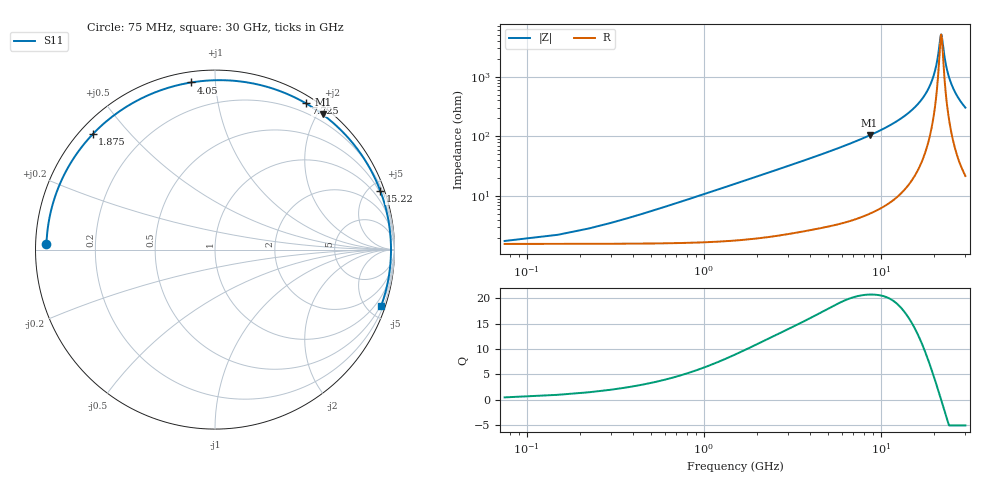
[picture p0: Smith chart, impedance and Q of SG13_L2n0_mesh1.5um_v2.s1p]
#  Hz  S  RI  R  50
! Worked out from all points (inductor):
!   400 points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, 75 MHz to 30 GHz, reference 50 ohm
!   read as one part to ground: L = 1.68 nH near 450 MHz
!   highest Q = 20.7 at 8.625 GHz (marker M1), where L = 1.91 nH
!   self-resonance near 21.9 GHz
!   S11 on the Smith chart (normalised r, x): 75 MHz: 0.03, +0.02; 1.875 GHz: 0.04, +0.40; 4.05 GHz: 0.05, +0.87; 7.725 GHz: 0.09, +1.80; 15.22 GHz: 0.40, +5.79; 30 GHz: 0.43, -6.05
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7.5e7  -0.939 0.0298
4.5e8  -0.9224 0.177
9e8  -0.8729 0.3446
1.425e9  -0.7814 0.518
1.875e9  -0.6818 0.6424
2.325e9  -0.5704 0.7426
2.775e9  -0.4537 0.8194
3.3e9  -0.3172 0.8825
3.825e9  -0.1852 0.9212
4.05e9  -0.1309 0.9315
4.425e9  -0.0441 0.9415
4.875e9  0.0537 0.9435
5.775e9  0.2268 0.9227
6.675e9  0.371 0.8798
7.575e9  0.4892 0.8247
7.725e9  0.5066 0.8148
8.625e9  0.5997 0.7533
9.9e9  0.7031 0.6641
1.1325e10  0.7886 0.5665
1.305e10  0.8617 0.455
1.5075e10  0.918 0.335
1.5225e10  0.9212 0.3266
1.695e10  0.9508 0.2335
1.8825e10  0.97 0.1399
2.0625e10  0.979 0.0563
2.2575e10  0.9803 -0.0286
2.6325e10  0.9633 -0.1788
3e10  0.9259 -0.313
